VERSION 5.7 ;
BUSBITCHARS "[]" ;
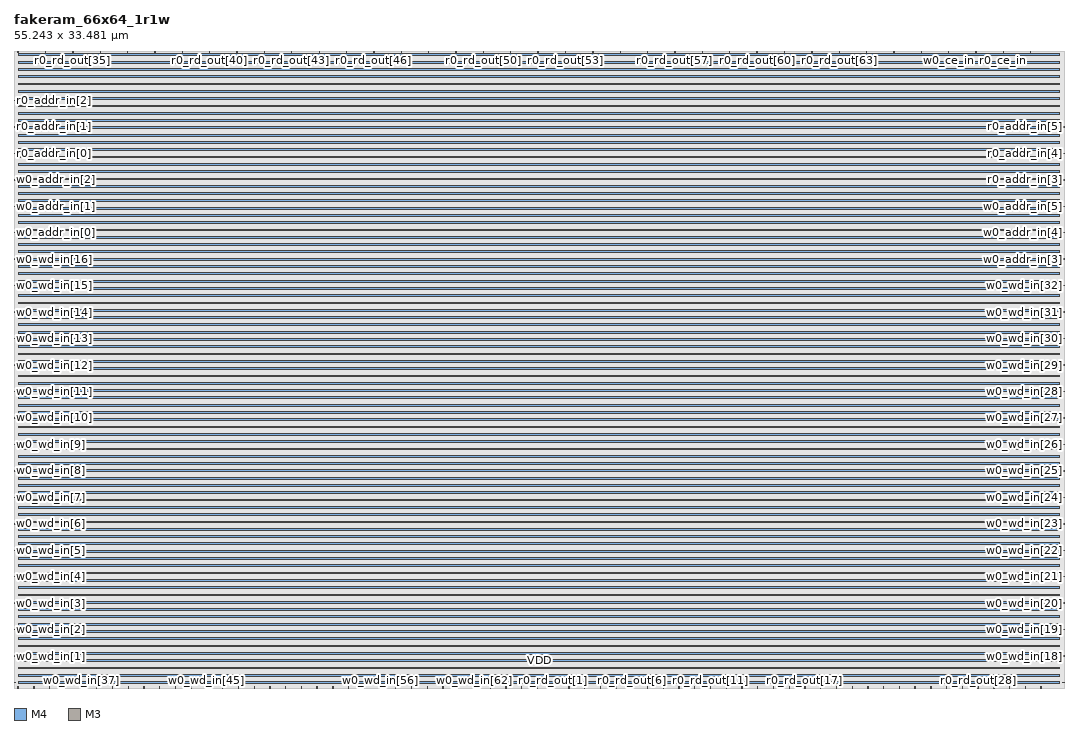
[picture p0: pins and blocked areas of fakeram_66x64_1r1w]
MACRO fakeram_66x64_1r1w
  FOREIGN fakeram_66x64_1r1w 0 0 ;
  SYMMETRY X Y R90 ;
  SIZE 55.243 BY 33.481 ;
  CLASS BLOCK ;
  PIN w0_wd_in[0]
    DIRECTION INPUT ;
    USE SIGNAL ;
    SHAPE ABUTMENT ;
    PORT
      LAYER M4 ;
      RECT 0.000 0.276 0.072 0.300 ;
    END
  END w0_wd_in[0]
  PIN w0_wd_in[1]
    DIRECTION INPUT ;
    USE SIGNAL ;
    SHAPE ABUTMENT ;
    PORT
      LAYER M4 ;
      RECT 0.000 1.668 0.072 1.692 ;
    END
  END w0_wd_in[1]
  PIN w0_wd_in[2]
    DIRECTION INPUT ;
    USE SIGNAL ;
    SHAPE ABUTMENT ;
    PORT
      LAYER M4 ;
      RECT 0.000 3.060 0.072 3.084 ;
    END
  END w0_wd_in[2]
  PIN w0_wd_in[3]
    DIRECTION INPUT ;
    USE SIGNAL ;
    SHAPE ABUTMENT ;
    PORT
      LAYER M4 ;
      RECT 0.000 4.452 0.072 4.476 ;
    END
  END w0_wd_in[3]
  PIN w0_wd_in[4]
    DIRECTION INPUT ;
    USE SIGNAL ;
    SHAPE ABUTMENT ;
    PORT
      LAYER M4 ;
      RECT 0.000 5.844 0.072 5.868 ;
    END
  END w0_wd_in[4]
  PIN w0_wd_in[5]
    DIRECTION INPUT ;
    USE SIGNAL ;
    SHAPE ABUTMENT ;
    PORT
      LAYER M4 ;
      RECT 0.000 7.236 0.072 7.260 ;
    END
  END w0_wd_in[5]
  PIN w0_wd_in[6]
    DIRECTION INPUT ;
    USE SIGNAL ;
    SHAPE ABUTMENT ;
    PORT
      LAYER M4 ;
      RECT 0.000 8.628 0.072 8.652 ;
    END
  END w0_wd_in[6]
  PIN w0_wd_in[7]
    DIRECTION INPUT ;
    USE SIGNAL ;
    SHAPE ABUTMENT ;
    PORT
      LAYER M4 ;
      RECT 0.000 10.020 0.072 10.044 ;
    END
  END w0_wd_in[7]
  PIN w0_wd_in[8]
    DIRECTION INPUT ;
    USE SIGNAL ;
    SHAPE ABUTMENT ;
    PORT
      LAYER M4 ;
      RECT 0.000 11.412 0.072 11.436 ;
    END
  END w0_wd_in[8]
  PIN w0_wd_in[9]
    DIRECTION INPUT ;
    USE SIGNAL ;
    SHAPE ABUTMENT ;
    PORT
      LAYER M4 ;
      RECT 0.000 12.804 0.072 12.828 ;
    END
  END w0_wd_in[9]
  PIN w0_wd_in[10]
    DIRECTION INPUT ;
    USE SIGNAL ;
    SHAPE ABUTMENT ;
    PORT
      LAYER M4 ;
      RECT 0.000 14.196 0.072 14.220 ;
    END
  END w0_wd_in[10]
  PIN w0_wd_in[11]
    DIRECTION INPUT ;
    USE SIGNAL ;
    SHAPE ABUTMENT ;
    PORT
      LAYER M4 ;
      RECT 0.000 15.588 0.072 15.612 ;
    END
  END w0_wd_in[11]
  PIN w0_wd_in[12]
    DIRECTION INPUT ;
    USE SIGNAL ;
    SHAPE ABUTMENT ;
    PORT
      LAYER M4 ;
      RECT 0.000 16.980 0.072 17.004 ;
    END
  END w0_wd_in[12]
  PIN w0_wd_in[13]
    DIRECTION INPUT ;
    USE SIGNAL ;
    SHAPE ABUTMENT ;
    PORT
      LAYER M4 ;
      RECT 0.000 18.372 0.072 18.396 ;
    END
  END w0_wd_in[13]
  PIN w0_wd_in[14]
    DIRECTION INPUT ;
    USE SIGNAL ;
    SHAPE ABUTMENT ;
    PORT
      LAYER M4 ;
      RECT 0.000 19.764 0.072 19.788 ;
    END
  END w0_wd_in[14]
  PIN w0_wd_in[15]
    DIRECTION INPUT ;
    USE SIGNAL ;
    SHAPE ABUTMENT ;
    PORT
      LAYER M4 ;
      RECT 0.000 21.156 0.072 21.180 ;
    END
  END w0_wd_in[15]
  PIN w0_wd_in[16]
    DIRECTION INPUT ;
    USE SIGNAL ;
    SHAPE ABUTMENT ;
    PORT
      LAYER M4 ;
      RECT 0.000 22.548 0.072 22.572 ;
    END
  END w0_wd_in[16]
  PIN w0_wd_in[17]
    DIRECTION INPUT ;
    USE SIGNAL ;
    SHAPE ABUTMENT ;
    PORT
      LAYER M4 ;
      RECT 55.171 0.276 55.243 0.300 ;
    END
  END w0_wd_in[17]
  PIN w0_wd_in[18]
    DIRECTION INPUT ;
    USE SIGNAL ;
    SHAPE ABUTMENT ;
    PORT
      LAYER M4 ;
      RECT 55.171 1.668 55.243 1.692 ;
    END
  END w0_wd_in[18]
  PIN w0_wd_in[19]
    DIRECTION INPUT ;
    USE SIGNAL ;
    SHAPE ABUTMENT ;
    PORT
      LAYER M4 ;
      RECT 55.171 3.060 55.243 3.084 ;
    END
  END w0_wd_in[19]
  PIN w0_wd_in[20]
    DIRECTION INPUT ;
    USE SIGNAL ;
    SHAPE ABUTMENT ;
    PORT
      LAYER M4 ;
      RECT 55.171 4.452 55.243 4.476 ;
    END
  END w0_wd_in[20]
  PIN w0_wd_in[21]
    DIRECTION INPUT ;
    USE SIGNAL ;
    SHAPE ABUTMENT ;
    PORT
      LAYER M4 ;
      RECT 55.171 5.844 55.243 5.868 ;
    END
  END w0_wd_in[21]
  PIN w0_wd_in[22]
    DIRECTION INPUT ;
    USE SIGNAL ;
    SHAPE ABUTMENT ;
    PORT
      LAYER M4 ;
      RECT 55.171 7.236 55.243 7.260 ;
    END
  END w0_wd_in[22]
  PIN w0_wd_in[23]
    DIRECTION INPUT ;
    USE SIGNAL ;
    SHAPE ABUTMENT ;
    PORT
      LAYER M4 ;
      RECT 55.171 8.628 55.243 8.652 ;
    END
  END w0_wd_in[23]
  PIN w0_wd_in[24]
    DIRECTION INPUT ;
    USE SIGNAL ;
    SHAPE ABUTMENT ;
    PORT
      LAYER M4 ;
      RECT 55.171 10.020 55.243 10.044 ;
    END
  END w0_wd_in[24]
  PIN w0_wd_in[25]
    DIRECTION INPUT ;
    USE SIGNAL ;
    SHAPE ABUTMENT ;
    PORT
      LAYER M4 ;
      RECT 55.171 11.412 55.243 11.436 ;
    END
  END w0_wd_in[25]
  PIN w0_wd_in[26]
    DIRECTION INPUT ;
    USE SIGNAL ;
    SHAPE ABUTMENT ;
    PORT
      LAYER M4 ;
      RECT 55.171 12.804 55.243 12.828 ;
    END
  END w0_wd_in[26]
  PIN w0_wd_in[27]
    DIRECTION INPUT ;
    USE SIGNAL ;
    SHAPE ABUTMENT ;
    PORT
      LAYER M4 ;
      RECT 55.171 14.196 55.243 14.220 ;
    END
  END w0_wd_in[27]
  PIN w0_wd_in[28]
    DIRECTION INPUT ;
    USE SIGNAL ;
    SHAPE ABUTMENT ;
    PORT
      LAYER M4 ;
      RECT 55.171 15.588 55.243 15.612 ;
    END
  END w0_wd_in[28]
  PIN w0_wd_in[29]
    DIRECTION INPUT ;
    USE SIGNAL ;
    SHAPE ABUTMENT ;
    PORT
      LAYER M4 ;
      RECT 55.171 16.980 55.243 17.004 ;
    END
  END w0_wd_in[29]
  PIN w0_wd_in[30]
    DIRECTION INPUT ;
    USE SIGNAL ;
    SHAPE ABUTMENT ;
    PORT
      LAYER M4 ;
      RECT 55.171 18.372 55.243 18.396 ;
    END
  END w0_wd_in[30]
  PIN w0_wd_in[31]
    DIRECTION INPUT ;
    USE SIGNAL ;
    SHAPE ABUTMENT ;
    PORT
      LAYER M4 ;
      RECT 55.171 19.764 55.243 19.788 ;
    END
  END w0_wd_in[31]
  PIN w0_wd_in[32]
    DIRECTION INPUT ;
    USE SIGNAL ;
    SHAPE ABUTMENT ;
    PORT
      LAYER M4 ;
      RECT 55.171 21.156 55.243 21.180 ;
    END
  END w0_wd_in[32]
  PIN w0_wd_in[33]
    DIRECTION INPUT ;
    USE SIGNAL ;
    SHAPE ABUTMENT ;
    PORT
      LAYER M3 ;
      RECT 0.207 0.000 0.225 0.054 ;
    END
  END w0_wd_in[33]
  PIN w0_wd_in[34]
    DIRECTION INPUT ;
    USE SIGNAL ;
    SHAPE ABUTMENT ;
    PORT
      LAYER M3 ;
      RECT 1.035 0.000 1.053 0.054 ;
    END
  END w0_wd_in[34]
  PIN w0_wd_in[35]
    DIRECTION INPUT ;
    USE SIGNAL ;
    SHAPE ABUTMENT ;
    PORT
      LAYER M3 ;
      RECT 1.863 0.000 1.881 0.054 ;
    END
  END w0_wd_in[35]
  PIN w0_wd_in[36]
    DIRECTION INPUT ;
    USE SIGNAL ;
    SHAPE ABUTMENT ;
    PORT
      LAYER M3 ;
      RECT 2.691 0.000 2.709 0.054 ;
    END
  END w0_wd_in[36]
  PIN w0_wd_in[37]
    DIRECTION INPUT ;
    USE SIGNAL ;
    SHAPE ABUTMENT ;
    PORT
      LAYER M3 ;
      RECT 3.519 0.000 3.537 0.054 ;
    END
  END w0_wd_in[37]
  PIN w0_wd_in[38]
    DIRECTION INPUT ;
    USE SIGNAL ;
    SHAPE ABUTMENT ;
    PORT
      LAYER M3 ;
      RECT 4.347 0.000 4.365 0.054 ;
    END
  END w0_wd_in[38]
  PIN w0_wd_in[39]
    DIRECTION INPUT ;
    USE SIGNAL ;
    SHAPE ABUTMENT ;
    PORT
      LAYER M3 ;
      RECT 5.175 0.000 5.193 0.054 ;
    END
  END w0_wd_in[39]
  PIN w0_wd_in[40]
    DIRECTION INPUT ;
    USE SIGNAL ;
    SHAPE ABUTMENT ;
    PORT
      LAYER M3 ;
      RECT 6.003 0.000 6.021 0.054 ;
    END
  END w0_wd_in[40]
  PIN w0_wd_in[41]
    DIRECTION INPUT ;
    USE SIGNAL ;
    SHAPE ABUTMENT ;
    PORT
      LAYER M3 ;
      RECT 6.831 0.000 6.849 0.054 ;
    END
  END w0_wd_in[41]
  PIN w0_wd_in[42]
    DIRECTION INPUT ;
    USE SIGNAL ;
    SHAPE ABUTMENT ;
    PORT
      LAYER M3 ;
      RECT 7.659 0.000 7.677 0.054 ;
    END
  END w0_wd_in[42]
  PIN w0_wd_in[43]
    DIRECTION INPUT ;
    USE SIGNAL ;
    SHAPE ABUTMENT ;
    PORT
      LAYER M3 ;
      RECT 8.487 0.000 8.505 0.054 ;
    END
  END w0_wd_in[43]
  PIN w0_wd_in[44]
    DIRECTION INPUT ;
    USE SIGNAL ;
    SHAPE ABUTMENT ;
    PORT
      LAYER M3 ;
      RECT 9.315 0.000 9.333 0.054 ;
    END
  END w0_wd_in[44]
  PIN w0_wd_in[45]
    DIRECTION INPUT ;
    USE SIGNAL ;
    SHAPE ABUTMENT ;
    PORT
      LAYER M3 ;
      RECT 10.143 0.000 10.161 0.054 ;
    END
  END w0_wd_in[45]
  PIN w0_wd_in[46]
    DIRECTION INPUT ;
    USE SIGNAL ;
    SHAPE ABUTMENT ;
    PORT
      LAYER M3 ;
      RECT 10.971 0.000 10.989 0.054 ;
    END
  END w0_wd_in[46]
  PIN w0_wd_in[47]
    DIRECTION INPUT ;
    USE SIGNAL ;
    SHAPE ABUTMENT ;
    PORT
      LAYER M3 ;
      RECT 11.799 0.000 11.817 0.054 ;
    END
  END w0_wd_in[47]
  PIN w0_wd_in[48]
    DIRECTION INPUT ;
    USE SIGNAL ;
    SHAPE ABUTMENT ;
    PORT
      LAYER M3 ;
      RECT 12.627 0.000 12.645 0.054 ;
    END
  END w0_wd_in[48]
  PIN w0_wd_in[49]
    DIRECTION INPUT ;
    USE SIGNAL ;
    SHAPE ABUTMENT ;
    PORT
      LAYER M3 ;
      RECT 13.455 0.000 13.473 0.054 ;
    END
  END w0_wd_in[49]
  PIN w0_wd_in[50]
    DIRECTION INPUT ;
    USE SIGNAL ;
    SHAPE ABUTMENT ;
    PORT
      LAYER M3 ;
      RECT 14.283 0.000 14.301 0.054 ;
    END
  END w0_wd_in[50]
  PIN w0_wd_in[51]
    DIRECTION INPUT ;
    USE SIGNAL ;
    SHAPE ABUTMENT ;
    PORT
      LAYER M3 ;
      RECT 15.111 0.000 15.129 0.054 ;
    END
  END w0_wd_in[51]
  PIN w0_wd_in[52]
    DIRECTION INPUT ;
    USE SIGNAL ;
    SHAPE ABUTMENT ;
    PORT
      LAYER M3 ;
      RECT 15.939 0.000 15.957 0.054 ;
    END
  END w0_wd_in[52]
  PIN w0_wd_in[53]
    DIRECTION INPUT ;
    USE SIGNAL ;
    SHAPE ABUTMENT ;
    PORT
      LAYER M3 ;
      RECT 16.767 0.000 16.785 0.054 ;
    END
  END w0_wd_in[53]
  PIN w0_wd_in[54]
    DIRECTION INPUT ;
    USE SIGNAL ;
    SHAPE ABUTMENT ;
    PORT
      LAYER M3 ;
      RECT 17.595 0.000 17.613 0.054 ;
    END
  END w0_wd_in[54]
  PIN w0_wd_in[55]
    DIRECTION INPUT ;
    USE SIGNAL ;
    SHAPE ABUTMENT ;
    PORT
      LAYER M3 ;
      RECT 18.423 0.000 18.441 0.054 ;
    END
  END w0_wd_in[55]
  PIN w0_wd_in[56]
    DIRECTION INPUT ;
    USE SIGNAL ;
    SHAPE ABUTMENT ;
    PORT
      LAYER M3 ;
      RECT 19.251 0.000 19.269 0.054 ;
    END
  END w0_wd_in[56]
  PIN w0_wd_in[57]
    DIRECTION INPUT ;
    USE SIGNAL ;
    SHAPE ABUTMENT ;
    PORT
      LAYER M3 ;
      RECT 20.079 0.000 20.097 0.054 ;
    END
  END w0_wd_in[57]
  PIN w0_wd_in[58]
    DIRECTION INPUT ;
    USE SIGNAL ;
    SHAPE ABUTMENT ;
    PORT
      LAYER M3 ;
      RECT 20.907 0.000 20.925 0.054 ;
    END
  END w0_wd_in[58]
  PIN w0_wd_in[59]
    DIRECTION INPUT ;
    USE SIGNAL ;
    SHAPE ABUTMENT ;
    PORT
      LAYER M3 ;
      RECT 21.735 0.000 21.753 0.054 ;
    END
  END w0_wd_in[59]
  PIN w0_wd_in[60]
    DIRECTION INPUT ;
    USE SIGNAL ;
    SHAPE ABUTMENT ;
    PORT
      LAYER M3 ;
      RECT 22.563 0.000 22.581 0.054 ;
    END
  END w0_wd_in[60]
  PIN w0_wd_in[61]
    DIRECTION INPUT ;
    USE SIGNAL ;
    SHAPE ABUTMENT ;
    PORT
      LAYER M3 ;
      RECT 23.391 0.000 23.409 0.054 ;
    END
  END w0_wd_in[61]
  PIN w0_wd_in[62]
    DIRECTION INPUT ;
    USE SIGNAL ;
    SHAPE ABUTMENT ;
    PORT
      LAYER M3 ;
      RECT 24.219 0.000 24.237 0.054 ;
    END
  END w0_wd_in[62]
  PIN w0_wd_in[63]
    DIRECTION INPUT ;
    USE SIGNAL ;
    SHAPE ABUTMENT ;
    PORT
      LAYER M3 ;
      RECT 25.047 0.000 25.065 0.054 ;
    END
  END w0_wd_in[63]
  PIN w0_wd_in[64]
    DIRECTION INPUT ;
    USE SIGNAL ;
    SHAPE ABUTMENT ;
    PORT
      LAYER M3 ;
      RECT 25.875 0.000 25.893 0.054 ;
    END
  END w0_wd_in[64]
  PIN w0_wd_in[65]
    DIRECTION INPUT ;
    USE SIGNAL ;
    SHAPE ABUTMENT ;
    PORT
      LAYER M3 ;
      RECT 26.703 0.000 26.721 0.054 ;
    END
  END w0_wd_in[65]
  PIN r0_rd_out[0]
    DIRECTION OUTPUT ;
    USE SIGNAL ;
    SHAPE ABUTMENT ;
    PORT
      LAYER M3 ;
      RECT 27.531 0.000 27.549 0.054 ;
    END
  END r0_rd_out[0]
  PIN r0_rd_out[1]
    DIRECTION OUTPUT ;
    USE SIGNAL ;
    SHAPE ABUTMENT ;
    PORT
      LAYER M3 ;
      RECT 28.359 0.000 28.377 0.054 ;
    END
  END r0_rd_out[1]
  PIN r0_rd_out[2]
    DIRECTION OUTPUT ;
    USE SIGNAL ;
    SHAPE ABUTMENT ;
    PORT
      LAYER M3 ;
      RECT 29.187 0.000 29.205 0.054 ;
    END
  END r0_rd_out[2]
  PIN r0_rd_out[3]
    DIRECTION OUTPUT ;
    USE SIGNAL ;
    SHAPE ABUTMENT ;
    PORT
      LAYER M3 ;
      RECT 30.015 0.000 30.033 0.054 ;
    END
  END r0_rd_out[3]
  PIN r0_rd_out[4]
    DIRECTION OUTPUT ;
    USE SIGNAL ;
    SHAPE ABUTMENT ;
    PORT
      LAYER M3 ;
      RECT 30.843 0.000 30.861 0.054 ;
    END
  END r0_rd_out[4]
  PIN r0_rd_out[5]
    DIRECTION OUTPUT ;
    USE SIGNAL ;
    SHAPE ABUTMENT ;
    PORT
      LAYER M3 ;
      RECT 31.671 0.000 31.689 0.054 ;
    END
  END r0_rd_out[5]
  PIN r0_rd_out[6]
    DIRECTION OUTPUT ;
    USE SIGNAL ;
    SHAPE ABUTMENT ;
    PORT
      LAYER M3 ;
      RECT 32.499 0.000 32.517 0.054 ;
    END
  END r0_rd_out[6]
  PIN r0_rd_out[7]
    DIRECTION OUTPUT ;
    USE SIGNAL ;
    SHAPE ABUTMENT ;
    PORT
      LAYER M3 ;
      RECT 33.327 0.000 33.345 0.054 ;
    END
  END r0_rd_out[7]
  PIN r0_rd_out[8]
    DIRECTION OUTPUT ;
    USE SIGNAL ;
    SHAPE ABUTMENT ;
    PORT
      LAYER M3 ;
      RECT 34.155 0.000 34.173 0.054 ;
    END
  END r0_rd_out[8]
  PIN r0_rd_out[9]
    DIRECTION OUTPUT ;
    USE SIGNAL ;
    SHAPE ABUTMENT ;
    PORT
      LAYER M3 ;
      RECT 34.983 0.000 35.001 0.054 ;
    END
  END r0_rd_out[9]
  PIN r0_rd_out[10]
    DIRECTION OUTPUT ;
    USE SIGNAL ;
    SHAPE ABUTMENT ;
    PORT
      LAYER M3 ;
      RECT 35.811 0.000 35.829 0.054 ;
    END
  END r0_rd_out[10]
  PIN r0_rd_out[11]
    DIRECTION OUTPUT ;
    USE SIGNAL ;
    SHAPE ABUTMENT ;
    PORT
      LAYER M3 ;
      RECT 36.639 0.000 36.657 0.054 ;
    END
  END r0_rd_out[11]
  PIN r0_rd_out[12]
    DIRECTION OUTPUT ;
    USE SIGNAL ;
    SHAPE ABUTMENT ;
    PORT
      LAYER M3 ;
      RECT 37.467 0.000 37.485 0.054 ;
    END
  END r0_rd_out[12]
  PIN r0_rd_out[13]
    DIRECTION OUTPUT ;
    USE SIGNAL ;
    SHAPE ABUTMENT ;
    PORT
      LAYER M3 ;
      RECT 38.295 0.000 38.313 0.054 ;
    END
  END r0_rd_out[13]
  PIN r0_rd_out[14]
    DIRECTION OUTPUT ;
    USE SIGNAL ;
    SHAPE ABUTMENT ;
    PORT
      LAYER M3 ;
      RECT 39.123 0.000 39.141 0.054 ;
    END
  END r0_rd_out[14]
  PIN r0_rd_out[15]
    DIRECTION OUTPUT ;
    USE SIGNAL ;
    SHAPE ABUTMENT ;
    PORT
      LAYER M3 ;
      RECT 39.951 0.000 39.969 0.054 ;
    END
  END r0_rd_out[15]
  PIN r0_rd_out[16]
    DIRECTION OUTPUT ;
    USE SIGNAL ;
    SHAPE ABUTMENT ;
    PORT
      LAYER M3 ;
      RECT 40.779 0.000 40.797 0.054 ;
    END
  END r0_rd_out[16]
  PIN r0_rd_out[17]
    DIRECTION OUTPUT ;
    USE SIGNAL ;
    SHAPE ABUTMENT ;
    PORT
      LAYER M3 ;
      RECT 41.607 0.000 41.625 0.054 ;
    END
  END r0_rd_out[17]
  PIN r0_rd_out[18]
    DIRECTION OUTPUT ;
    USE SIGNAL ;
    SHAPE ABUTMENT ;
    PORT
      LAYER M3 ;
      RECT 42.435 0.000 42.453 0.054 ;
    END
  END r0_rd_out[18]
  PIN r0_rd_out[19]
    DIRECTION OUTPUT ;
    USE SIGNAL ;
    SHAPE ABUTMENT ;
    PORT
      LAYER M3 ;
      RECT 43.263 0.000 43.281 0.054 ;
    END
  END r0_rd_out[19]
  PIN r0_rd_out[20]
    DIRECTION OUTPUT ;
    USE SIGNAL ;
    SHAPE ABUTMENT ;
    PORT
      LAYER M3 ;
      RECT 44.091 0.000 44.109 0.054 ;
    END
  END r0_rd_out[20]
  PIN r0_rd_out[21]
    DIRECTION OUTPUT ;
    USE SIGNAL ;
    SHAPE ABUTMENT ;
    PORT
      LAYER M3 ;
      RECT 44.919 0.000 44.937 0.054 ;
    END
  END r0_rd_out[21]
  PIN r0_rd_out[22]
    DIRECTION OUTPUT ;
    USE SIGNAL ;
    SHAPE ABUTMENT ;
    PORT
      LAYER M3 ;
      RECT 45.747 0.000 45.765 0.054 ;
    END
  END r0_rd_out[22]
  PIN r0_rd_out[23]
    DIRECTION OUTPUT ;
    USE SIGNAL ;
    SHAPE ABUTMENT ;
    PORT
      LAYER M3 ;
      RECT 46.575 0.000 46.593 0.054 ;
    END
  END r0_rd_out[23]
  PIN r0_rd_out[24]
    DIRECTION OUTPUT ;
    USE SIGNAL ;
    SHAPE ABUTMENT ;
    PORT
      LAYER M3 ;
      RECT 47.403 0.000 47.421 0.054 ;
    END
  END r0_rd_out[24]
  PIN r0_rd_out[25]
    DIRECTION OUTPUT ;
    USE SIGNAL ;
    SHAPE ABUTMENT ;
    PORT
      LAYER M3 ;
      RECT 48.231 0.000 48.249 0.054 ;
    END
  END r0_rd_out[25]
  PIN r0_rd_out[26]
    DIRECTION OUTPUT ;
    USE SIGNAL ;
    SHAPE ABUTMENT ;
    PORT
      LAYER M3 ;
      RECT 49.059 0.000 49.077 0.054 ;
    END
  END r0_rd_out[26]
  PIN r0_rd_out[27]
    DIRECTION OUTPUT ;
    USE SIGNAL ;
    SHAPE ABUTMENT ;
    PORT
      LAYER M3 ;
      RECT 49.887 0.000 49.905 0.054 ;
    END
  END r0_rd_out[27]
  PIN r0_rd_out[28]
    DIRECTION OUTPUT ;
    USE SIGNAL ;
    SHAPE ABUTMENT ;
    PORT
      LAYER M3 ;
      RECT 50.715 0.000 50.733 0.054 ;
    END
  END r0_rd_out[28]
  PIN r0_rd_out[29]
    DIRECTION OUTPUT ;
    USE SIGNAL ;
    SHAPE ABUTMENT ;
    PORT
      LAYER M3 ;
      RECT 51.543 0.000 51.561 0.054 ;
    END
  END r0_rd_out[29]
  PIN r0_rd_out[30]
    DIRECTION OUTPUT ;
    USE SIGNAL ;
    SHAPE ABUTMENT ;
    PORT
      LAYER M3 ;
      RECT 52.371 0.000 52.389 0.054 ;
    END
  END r0_rd_out[30]
  PIN r0_rd_out[31]
    DIRECTION OUTPUT ;
    USE SIGNAL ;
    SHAPE ABUTMENT ;
    PORT
      LAYER M3 ;
      RECT 53.199 0.000 53.217 0.054 ;
    END
  END r0_rd_out[31]
  PIN r0_rd_out[32]
    DIRECTION OUTPUT ;
    USE SIGNAL ;
    SHAPE ABUTMENT ;
    PORT
      LAYER M3 ;
      RECT 54.027 0.000 54.045 0.054 ;
    END
  END r0_rd_out[32]
  PIN r0_rd_out[33]
    DIRECTION OUTPUT ;
    USE SIGNAL ;
    SHAPE ABUTMENT ;
    PORT
      LAYER M3 ;
      RECT 0.207 33.427 0.225 33.481 ;
    END
  END r0_rd_out[33]
  PIN r0_rd_out[34]
    DIRECTION OUTPUT ;
    USE SIGNAL ;
    SHAPE ABUTMENT ;
    PORT
      LAYER M3 ;
      RECT 1.647 33.427 1.665 33.481 ;
    END
  END r0_rd_out[34]
  PIN r0_rd_out[35]
    DIRECTION OUTPUT ;
    USE SIGNAL ;
    SHAPE ABUTMENT ;
    PORT
      LAYER M3 ;
      RECT 3.087 33.427 3.105 33.481 ;
    END
  END r0_rd_out[35]
  PIN r0_rd_out[36]
    DIRECTION OUTPUT ;
    USE SIGNAL ;
    SHAPE ABUTMENT ;
    PORT
      LAYER M3 ;
      RECT 4.527 33.427 4.545 33.481 ;
    END
  END r0_rd_out[36]
  PIN r0_rd_out[37]
    DIRECTION OUTPUT ;
    USE SIGNAL ;
    SHAPE ABUTMENT ;
    PORT
      LAYER M3 ;
      RECT 5.967 33.427 5.985 33.481 ;
    END
  END r0_rd_out[37]
  PIN r0_rd_out[38]
    DIRECTION OUTPUT ;
    USE SIGNAL ;
    SHAPE ABUTMENT ;
    PORT
      LAYER M3 ;
      RECT 7.407 33.427 7.425 33.481 ;
    END
  END r0_rd_out[38]
  PIN r0_rd_out[39]
    DIRECTION OUTPUT ;
    USE SIGNAL ;
    SHAPE ABUTMENT ;
    PORT
      LAYER M3 ;
      RECT 8.847 33.427 8.865 33.481 ;
    END
  END r0_rd_out[39]
  PIN r0_rd_out[40]
    DIRECTION OUTPUT ;
    USE SIGNAL ;
    SHAPE ABUTMENT ;
    PORT
      LAYER M3 ;
      RECT 10.287 33.427 10.305 33.481 ;
    END
  END r0_rd_out[40]
  PIN r0_rd_out[41]
    DIRECTION OUTPUT ;
    USE SIGNAL ;
    SHAPE ABUTMENT ;
    PORT
      LAYER M3 ;
      RECT 11.727 33.427 11.745 33.481 ;
    END
  END r0_rd_out[41]
  PIN r0_rd_out[42]
    DIRECTION OUTPUT ;
    USE SIGNAL ;
    SHAPE ABUTMENT ;
    PORT
      LAYER M3 ;
      RECT 13.167 33.427 13.185 33.481 ;
    END
  END r0_rd_out[42]
  PIN r0_rd_out[43]
    DIRECTION OUTPUT ;
    USE SIGNAL ;
    SHAPE ABUTMENT ;
    PORT
      LAYER M3 ;
      RECT 14.607 33.427 14.625 33.481 ;
    END
  END r0_rd_out[43]
  PIN r0_rd_out[44]
    DIRECTION OUTPUT ;
    USE SIGNAL ;
    SHAPE ABUTMENT ;
    PORT
      LAYER M3 ;
      RECT 16.047 33.427 16.065 33.481 ;
    END
  END r0_rd_out[44]
  PIN r0_rd_out[45]
    DIRECTION OUTPUT ;
    USE SIGNAL ;
    SHAPE ABUTMENT ;
    PORT
      LAYER M3 ;
      RECT 17.487 33.427 17.505 33.481 ;
    END
  END r0_rd_out[45]
  PIN r0_rd_out[46]
    DIRECTION OUTPUT ;
    USE SIGNAL ;
    SHAPE ABUTMENT ;
    PORT
      LAYER M3 ;
      RECT 18.927 33.427 18.945 33.481 ;
    END
  END r0_rd_out[46]
  PIN r0_rd_out[47]
    DIRECTION OUTPUT ;
    USE SIGNAL ;
    SHAPE ABUTMENT ;
    PORT
      LAYER M3 ;
      RECT 20.367 33.427 20.385 33.481 ;
    END
  END r0_rd_out[47]
  PIN r0_rd_out[48]
    DIRECTION OUTPUT ;
    USE SIGNAL ;
    SHAPE ABUTMENT ;
    PORT
      LAYER M3 ;
      RECT 21.807 33.427 21.825 33.481 ;
    END
  END r0_rd_out[48]
  PIN r0_rd_out[49]
    DIRECTION OUTPUT ;
    USE SIGNAL ;
    SHAPE ABUTMENT ;
    PORT
      LAYER M3 ;
      RECT 23.247 33.427 23.265 33.481 ;
    END
  END r0_rd_out[49]
  PIN r0_rd_out[50]
    DIRECTION OUTPUT ;
    USE SIGNAL ;
    SHAPE ABUTMENT ;
    PORT
      LAYER M3 ;
      RECT 24.687 33.427 24.705 33.481 ;
    END
  END r0_rd_out[50]
  PIN r0_rd_out[51]
    DIRECTION OUTPUT ;
    USE SIGNAL ;
    SHAPE ABUTMENT ;
    PORT
      LAYER M3 ;
      RECT 26.127 33.427 26.145 33.481 ;
    END
  END r0_rd_out[51]
  PIN r0_rd_out[52]
    DIRECTION OUTPUT ;
    USE SIGNAL ;
    SHAPE ABUTMENT ;
    PORT
      LAYER M3 ;
      RECT 27.567 33.427 27.585 33.481 ;
    END
  END r0_rd_out[52]
  PIN r0_rd_out[53]
    DIRECTION OUTPUT ;
    USE SIGNAL ;
    SHAPE ABUTMENT ;
    PORT
      LAYER M3 ;
      RECT 29.007 33.427 29.025 33.481 ;
    END
  END r0_rd_out[53]
  PIN r0_rd_out[54]
    DIRECTION OUTPUT ;
    USE SIGNAL ;
    SHAPE ABUTMENT ;
    PORT
      LAYER M3 ;
      RECT 30.447 33.427 30.465 33.481 ;
    END
  END r0_rd_out[54]
  PIN r0_rd_out[55]
    DIRECTION OUTPUT ;
    USE SIGNAL ;
    SHAPE ABUTMENT ;
    PORT
      LAYER M3 ;
      RECT 31.887 33.427 31.905 33.481 ;
    END
  END r0_rd_out[55]
  PIN r0_rd_out[56]
    DIRECTION OUTPUT ;
    USE SIGNAL ;
    SHAPE ABUTMENT ;
    PORT
      LAYER M3 ;
      RECT 33.327 33.427 33.345 33.481 ;
    END
  END r0_rd_out[56]
  PIN r0_rd_out[57]
    DIRECTION OUTPUT ;
    USE SIGNAL ;
    SHAPE ABUTMENT ;
    PORT
      LAYER M3 ;
      RECT 34.767 33.427 34.785 33.481 ;
    END
  END r0_rd_out[57]
  PIN r0_rd_out[58]
    DIRECTION OUTPUT ;
    USE SIGNAL ;
    SHAPE ABUTMENT ;
    PORT
      LAYER M3 ;
      RECT 36.207 33.427 36.225 33.481 ;
    END
  END r0_rd_out[58]
  PIN r0_rd_out[59]
    DIRECTION OUTPUT ;
    USE SIGNAL ;
    SHAPE ABUTMENT ;
    PORT
      LAYER M3 ;
      RECT 37.647 33.427 37.665 33.481 ;
    END
  END r0_rd_out[59]
  PIN r0_rd_out[60]
    DIRECTION OUTPUT ;
    USE SIGNAL ;
    SHAPE ABUTMENT ;
    PORT
      LAYER M3 ;
      RECT 39.087 33.427 39.105 33.481 ;
    END
  END r0_rd_out[60]
  PIN r0_rd_out[61]
    DIRECTION OUTPUT ;
    USE SIGNAL ;
    SHAPE ABUTMENT ;
    PORT
      LAYER M3 ;
      RECT 40.527 33.427 40.545 33.481 ;
    END
  END r0_rd_out[61]
  PIN r0_rd_out[62]
    DIRECTION OUTPUT ;
    USE SIGNAL ;
    SHAPE ABUTMENT ;
    PORT
      LAYER M3 ;
      RECT 41.967 33.427 41.985 33.481 ;
    END
  END r0_rd_out[62]
  PIN r0_rd_out[63]
    DIRECTION OUTPUT ;
    USE SIGNAL ;
    SHAPE ABUTMENT ;
    PORT
      LAYER M3 ;
      RECT 43.407 33.427 43.425 33.481 ;
    END
  END r0_rd_out[63]
  PIN r0_rd_out[64]
    DIRECTION OUTPUT ;
    USE SIGNAL ;
    SHAPE ABUTMENT ;
    PORT
      LAYER M3 ;
      RECT 44.847 33.427 44.865 33.481 ;
    END
  END r0_rd_out[64]
  PIN r0_rd_out[65]
    DIRECTION OUTPUT ;
    USE SIGNAL ;
    SHAPE ABUTMENT ;
    PORT
      LAYER M3 ;
      RECT 46.287 33.427 46.305 33.481 ;
    END
  END r0_rd_out[65]
  PIN w0_addr_in[0]
    DIRECTION INPUT ;
    USE SIGNAL ;
    SHAPE ABUTMENT ;
    PORT
      LAYER M4 ;
      RECT 0.000 23.940 0.072 23.964 ;
    END
  END w0_addr_in[0]
  PIN w0_addr_in[1]
    DIRECTION INPUT ;
    USE SIGNAL ;
    SHAPE ABUTMENT ;
    PORT
      LAYER M4 ;
      RECT 0.000 25.332 0.072 25.356 ;
    END
  END w0_addr_in[1]
  PIN w0_addr_in[2]
    DIRECTION INPUT ;
    USE SIGNAL ;
    SHAPE ABUTMENT ;
    PORT
      LAYER M4 ;
      RECT 0.000 26.724 0.072 26.748 ;
    END
  END w0_addr_in[2]
  PIN w0_addr_in[3]
    DIRECTION INPUT ;
    USE SIGNAL ;
    SHAPE ABUTMENT ;
    PORT
      LAYER M4 ;
      RECT 55.171 22.548 55.243 22.572 ;
    END
  END w0_addr_in[3]
  PIN w0_addr_in[4]
    DIRECTION INPUT ;
    USE SIGNAL ;
    SHAPE ABUTMENT ;
    PORT
      LAYER M4 ;
      RECT 55.171 23.940 55.243 23.964 ;
    END
  END w0_addr_in[4]
  PIN w0_addr_in[5]
    DIRECTION INPUT ;
    USE SIGNAL ;
    SHAPE ABUTMENT ;
    PORT
      LAYER M4 ;
      RECT 55.171 25.332 55.243 25.356 ;
    END
  END w0_addr_in[5]
  PIN r0_addr_in[0]
    DIRECTION INPUT ;
    USE SIGNAL ;
    SHAPE ABUTMENT ;
    PORT
      LAYER M4 ;
      RECT 0.000 28.116 0.072 28.140 ;
    END
  END r0_addr_in[0]
  PIN r0_addr_in[1]
    DIRECTION INPUT ;
    USE SIGNAL ;
    SHAPE ABUTMENT ;
    PORT
      LAYER M4 ;
      RECT 0.000 29.508 0.072 29.532 ;
    END
  END r0_addr_in[1]
  PIN r0_addr_in[2]
    DIRECTION INPUT ;
    USE SIGNAL ;
    SHAPE ABUTMENT ;
    PORT
      LAYER M4 ;
      RECT 0.000 30.900 0.072 30.924 ;
    END
  END r0_addr_in[2]
  PIN r0_addr_in[3]
    DIRECTION INPUT ;
    USE SIGNAL ;
    SHAPE ABUTMENT ;
    PORT
      LAYER M4 ;
      RECT 55.171 26.724 55.243 26.748 ;
    END
  END r0_addr_in[3]
  PIN r0_addr_in[4]
    DIRECTION INPUT ;
    USE SIGNAL ;
    SHAPE ABUTMENT ;
    PORT
      LAYER M4 ;
      RECT 55.171 28.116 55.243 28.140 ;
    END
  END r0_addr_in[4]
  PIN r0_addr_in[5]
    DIRECTION INPUT ;
    USE SIGNAL ;
    SHAPE ABUTMENT ;
    PORT
      LAYER M4 ;
      RECT 55.171 29.508 55.243 29.532 ;
    END
  END r0_addr_in[5]
  PIN w0_we_in
    DIRECTION INPUT ;
    USE SIGNAL ;
    SHAPE ABUTMENT ;
    PORT
      LAYER M3 ;
      RECT 47.727 33.427 47.745 33.481 ;
    END
  END w0_we_in
  PIN w0_ce_in
    DIRECTION INPUT ;
    USE SIGNAL ;
    SHAPE ABUTMENT ;
    PORT
      LAYER M3 ;
      RECT 49.167 33.427 49.185 33.481 ;
    END
  END w0_ce_in
  PIN w0_clk
    DIRECTION INPUT ;
    USE SIGNAL ;
    SHAPE ABUTMENT ;
    PORT
      LAYER M3 ;
      RECT 50.607 33.427 50.625 33.481 ;
    END
  END w0_clk
  PIN r0_ce_in
    DIRECTION INPUT ;
    USE SIGNAL ;
    SHAPE ABUTMENT ;
    PORT
      LAYER M3 ;
      RECT 52.047 33.427 52.065 33.481 ;
    END
  END r0_ce_in
  PIN r0_clk
    DIRECTION INPUT ;
    USE SIGNAL ;
    SHAPE ABUTMENT ;
    PORT
      LAYER M3 ;
      RECT 53.487 33.427 53.505 33.481 ;
    END
  END r0_clk
  PIN VSS
    DIRECTION INOUT ;
    USE GROUND ;
    PORT
      LAYER M4 ;
      RECT 0.216 0.240 55.027 0.336 ;
      RECT 0.216 1.008 55.027 1.104 ;
      RECT 0.216 1.776 55.027 1.872 ;
      RECT 0.216 2.544 55.027 2.640 ;
      RECT 0.216 3.312 55.027 3.408 ;
      RECT 0.216 4.080 55.027 4.176 ;
      RECT 0.216 4.848 55.027 4.944 ;
      RECT 0.216 5.616 55.027 5.712 ;
      RECT 0.216 6.384 55.027 6.480 ;
      RECT 0.216 7.152 55.027 7.248 ;
      RECT 0.216 7.920 55.027 8.016 ;
      RECT 0.216 8.688 55.027 8.784 ;
      RECT 0.216 9.456 55.027 9.552 ;
      RECT 0.216 10.224 55.027 10.320 ;
      RECT 0.216 10.992 55.027 11.088 ;
      RECT 0.216 11.760 55.027 11.856 ;
      RECT 0.216 12.528 55.027 12.624 ;
      RECT 0.216 13.296 55.027 13.392 ;
      RECT 0.216 14.064 55.027 14.160 ;
      RECT 0.216 14.832 55.027 14.928 ;
      RECT 0.216 15.600 55.027 15.696 ;
      RECT 0.216 16.368 55.027 16.464 ;
      RECT 0.216 17.136 55.027 17.232 ;
      RECT 0.216 17.904 55.027 18.000 ;
      RECT 0.216 18.672 55.027 18.768 ;
      RECT 0.216 19.440 55.027 19.536 ;
      RECT 0.216 20.208 55.027 20.304 ;
      RECT 0.216 20.976 55.027 21.072 ;
      RECT 0.216 21.744 55.027 21.840 ;
      RECT 0.216 22.512 55.027 22.608 ;
      RECT 0.216 23.280 55.027 23.376 ;
      RECT 0.216 24.048 55.027 24.144 ;
      RECT 0.216 24.816 55.027 24.912 ;
      RECT 0.216 25.584 55.027 25.680 ;
      RECT 0.216 26.352 55.027 26.448 ;
      RECT 0.216 27.120 55.027 27.216 ;
      RECT 0.216 27.888 55.027 27.984 ;
      RECT 0.216 28.656 55.027 28.752 ;
      RECT 0.216 29.424 55.027 29.520 ;
      RECT 0.216 30.192 55.027 30.288 ;
      RECT 0.216 30.960 55.027 31.056 ;
      RECT 0.216 31.728 55.027 31.824 ;
      RECT 0.216 32.496 55.027 32.592 ;
      RECT 0.216 33.264 55.027 33.360 ;
    END
  END VSS
  PIN VDD
    DIRECTION INOUT ;
    USE POWER ;
    PORT
      LAYER M4 ;
      RECT 0.216 0.624 55.027 0.720 ;
      RECT 0.216 1.392 55.027 1.488 ;
      RECT 0.216 2.160 55.027 2.256 ;
      RECT 0.216 2.928 55.027 3.024 ;
      RECT 0.216 3.696 55.027 3.792 ;
      RECT 0.216 4.464 55.027 4.560 ;
      RECT 0.216 5.232 55.027 5.328 ;
      RECT 0.216 6.000 55.027 6.096 ;
      RECT 0.216 6.768 55.027 6.864 ;
      RECT 0.216 7.536 55.027 7.632 ;
      RECT 0.216 8.304 55.027 8.400 ;
      RECT 0.216 9.072 55.027 9.168 ;
      RECT 0.216 9.840 55.027 9.936 ;
      RECT 0.216 10.608 55.027 10.704 ;
      RECT 0.216 11.376 55.027 11.472 ;
      RECT 0.216 12.144 55.027 12.240 ;
      RECT 0.216 12.912 55.027 13.008 ;
      RECT 0.216 13.680 55.027 13.776 ;
      RECT 0.216 14.448 55.027 14.544 ;
      RECT 0.216 15.216 55.027 15.312 ;
      RECT 0.216 15.984 55.027 16.080 ;
      RECT 0.216 16.752 55.027 16.848 ;
      RECT 0.216 17.520 55.027 17.616 ;
      RECT 0.216 18.288 55.027 18.384 ;
      RECT 0.216 19.056 55.027 19.152 ;
      RECT 0.216 19.824 55.027 19.920 ;
      RECT 0.216 20.592 55.027 20.688 ;
      RECT 0.216 21.360 55.027 21.456 ;
      RECT 0.216 22.128 55.027 22.224 ;
      RECT 0.216 22.896 55.027 22.992 ;
      RECT 0.216 23.664 55.027 23.760 ;
      RECT 0.216 24.432 55.027 24.528 ;
      RECT 0.216 25.200 55.027 25.296 ;
      RECT 0.216 25.968 55.027 26.064 ;
      RECT 0.216 26.736 55.027 26.832 ;
      RECT 0.216 27.504 55.027 27.600 ;
      RECT 0.216 28.272 55.027 28.368 ;
      RECT 0.216 29.040 55.027 29.136 ;
      RECT 0.216 29.808 55.027 29.904 ;
      RECT 0.216 30.576 55.027 30.672 ;
      RECT 0.216 31.344 55.027 31.440 ;
      RECT 0.216 32.112 55.027 32.208 ;
      RECT 0.216 32.880 55.027 32.976 ;
    END
  END VDD
  OBS
    LAYER M1 ;
    RECT 0 0 55.243 33.481 ;
    LAYER M2 ;
    RECT 0 0 55.243 33.481 ;
    LAYER M3 ;
    RECT 0 0 55.243 33.481 ;
    LAYER M4 ;
    RECT 0 0 55.243 33.481 ;
  END
END fakeram_66x64_1r1w

END LIBRARY
